One B-rep face of a CAD part: STEP entity #21012.
In plain terms, the planar face has unit normal (0, 0, -1).
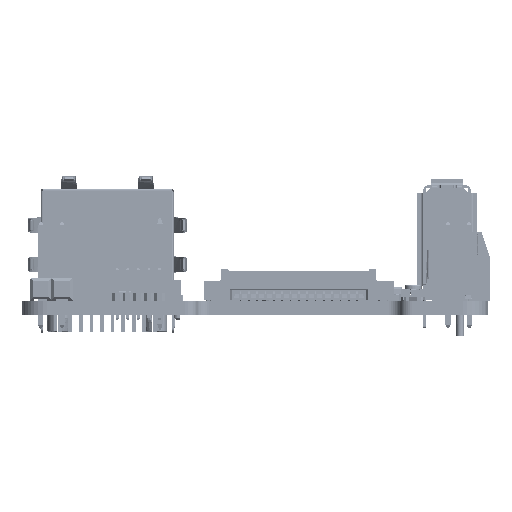
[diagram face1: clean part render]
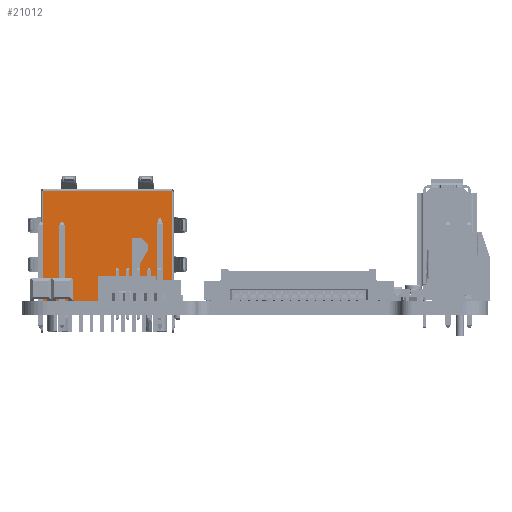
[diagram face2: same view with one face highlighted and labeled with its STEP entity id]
Its self-contained STEP definition (entity closure, numbers rounded to 3 decimals):
#18164 = VERTEX_POINT('',#18165);
#18165 = CARTESIAN_POINT('',(-7.775,-6.7,0.));
#18172 = EDGE_CURVE('',#18164,#18173,#18175,.T.);
#18173 = VERTEX_POINT('',#18174);
#18174 = CARTESIAN_POINT('',(7.775,-6.7,0.));
#18175 = LINE('',#18176,#18177);
#18176 = CARTESIAN_POINT('',(0.,-6.7,0.));
#18177 = VECTOR('',#18178,1.);
#18178 = DIRECTION('',(1.,0.,0.));
#21012 = ADVANCED_FACE('',(#21013),#21038,.F.);
#21013 = FACE_BOUND('',#21014,.T.);
#21014 = EDGE_LOOP('',(#21015,#21023,#21031,#21037));
#21015 = ORIENTED_EDGE('',*,*,#21016,.F.);
#21016 = EDGE_CURVE('',#21017,#18164,#21019,.T.);
#21017 = VERTEX_POINT('',#21018);
#21018 = CARTESIAN_POINT('',(-7.775,6.55,0.));
#21019 = LINE('',#21020,#21021);
#21020 = CARTESIAN_POINT('',(-7.775,0.,0.));
#21021 = VECTOR('',#21022,1.);
#21022 = DIRECTION('',(0.,-1.,0.));
#21023 = ORIENTED_EDGE('',*,*,#21024,.F.);
#21024 = EDGE_CURVE('',#21025,#21017,#21027,.T.);
#21025 = VERTEX_POINT('',#21026);
#21026 = CARTESIAN_POINT('',(7.775,6.55,0.));
#21027 = LINE('',#21028,#21029);
#21028 = CARTESIAN_POINT('',(0.,6.55,0.));
#21029 = VECTOR('',#21030,1.);
#21030 = DIRECTION('',(-1.,0.,0.));
#21031 = ORIENTED_EDGE('',*,*,#21032,.F.);
#21032 = EDGE_CURVE('',#18173,#21025,#21033,.T.);
#21033 = LINE('',#21034,#21035);
#21034 = CARTESIAN_POINT('',(7.775,0.,0.));
#21035 = VECTOR('',#21036,1.);
#21036 = DIRECTION('',(0.,1.,0.));
#21037 = ORIENTED_EDGE('',*,*,#18172,.F.);
#21038 = PLANE('',#21039);
#21039 = AXIS2_PLACEMENT_3D('',#21040,#21041,#21042);
#21040 = CARTESIAN_POINT('',(0.,0.,0.));
#21041 = DIRECTION('',(0.,0.,1.));
#21042 = DIRECTION('',(1.,0.,-0.));
